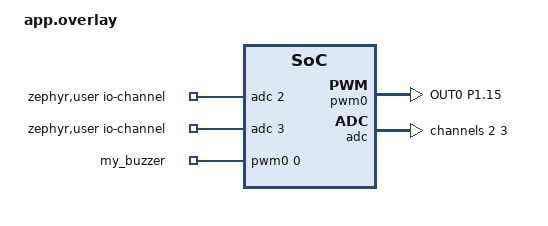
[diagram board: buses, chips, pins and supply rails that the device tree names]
/ {
    aliases {
        my-buzzer = &my_buzzer;
    };

    zephyr,user {
        io-channels = <&adc 2>,
                      <&adc 3>;
    };

    pwm_leds {
        compatible = "pwm-leds";
        my_buzzer: my_buzzer {
            pwms = <&pwm0 0 PWM_MSEC(1) PWM_POLARITY_NORMAL>;
        };
    };
};

&pinctrl {
    pwm0_default: pwm0_default {
        group1 {
            psels = <NRF_PSEL(PWM_OUT0, 1, 15)>;
        };
    };

    pwm0_sleep: pwm0_sleep {
        group1 {
            psels = <NRF_PSEL(PWM_OUT0, 1, 15)>;
            low-power-enable;
        };
    };
};

&pwm0 {
    status = "okay";
    pinctrl-0 = <&pwm0_default>;
    pinctrl-1 = <&pwm0_sleep>;
    pinctrl-names = "default", "sleep";
};

&adc {
    status = "okay";
    #address-cells = <1>;
    #size-cells = <0>;

    channel@2 {
        reg = <2>;
        zephyr,gain = "ADC_GAIN_1_6";
        zephyr,reference = "ADC_REF_INTERNAL";
        zephyr,acquisition-time = <ADC_ACQ_TIME_DEFAULT>;
        zephyr,input-positive = <2>;
        zephyr,resolution = <12>;
    };

    channel@3 {
        reg = <3>;
        zephyr,gain = "ADC_GAIN_1_6";
        zephyr,reference = "ADC_REF_INTERNAL";
        zephyr,acquisition-time = <ADC_ACQ_TIME_DEFAULT>;
        zephyr,input-positive = <3>;
        zephyr,resolution = <12>;
    };
};
